! (c) 2009  Infineon Technologies AG, Munich
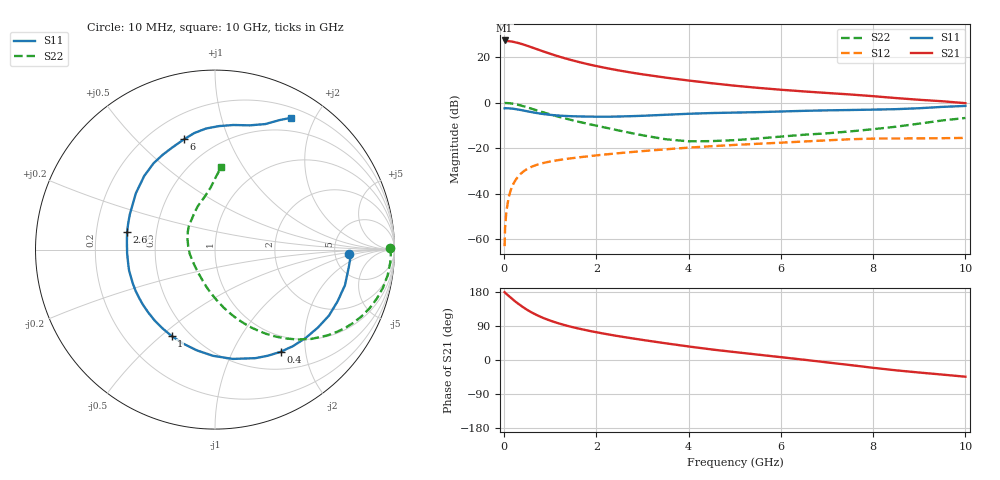
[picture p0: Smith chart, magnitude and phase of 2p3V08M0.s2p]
! Infineon Technologies  Discrete & RF Semiconductors
! BFP420
! VCE =  3.0 V,  IC =  8.0 mA
! Common Emitter S-Parameters:  Nov 2009
# GHz  S  MA  R  50
!  f  S11  S21  S12  S22
! GHz  MAG  ANG  MAG  ANG  MAG  ANG  MAG  ANG
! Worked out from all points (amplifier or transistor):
!   46 points, 10 MHz to 10 GHz, reference 50 ohm
!   highest |S21| = 27.3 dB at 10 MHz (marker M1)
!   |S21| within 3 dB of that: start of sweep to 594.4 MHz
!   unconditionally stable (mu >= 1): start of sweep to 10.1 MHz; 2.569 GHz to end of sweep
!   at 300 MHz: K = 0.16, MSG = 29.4 dB, |S12| = -32.6 dB
!   at 1.7 GHz: K = 0.75, MSG = 20.7 dB, |S12| = -23.9 dB
!   at 10 GHz: K = 1.10, MAG = 5.7 dB, |S12| = -15.5 dB
!   lowest NFmin = 0.79 dB at 900 MHz
!   S11 on the Smith chart (normalised r, x): 10 MHz: 6.91, -0.70; 400 MHz: 0.75, -1.57; 1 GHz: 0.40, -0.54; 2.6 GHz: 0.34, +0.09; 6 GHz: 0.34, +0.70; 10 GHz: 0.32, +1.68
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0.01  0.7496 -1.7  23.25 179.0  0.0007 60.7  0.9755 0.6
0.02  0.7566 -3.0  22.61 177.7  0.0018 79.4  0.9801 -1.6
0.05  0.7518 -7.5  22.56 174.3  0.0042 80.0  0.9794 -4.1
0.1  0.7508 -15.3  22.46 169.1  0.0085 80.8  0.9724 -8.5
0.2  0.7337 -30.1  21.67 158.7  0.0164 75.1  0.9424 -16.8
0.3  0.7055 -44.2  20.52 149.0  0.0235 69.0  0.8973 -24.5
0.4  0.6768 -57.3  19.17 140.3  0.0296 63.5  0.8436 -31.4
0.5  0.6456 -69.5  17.75 132.3  0.0348 58.9  0.7873 -37.4
0.7  0.592 -91.0  15.09 119.0  0.0427 51.8  0.6803 -47.4
0.8  0.5706 -100.2  13.88 113.4  0.0458 49.1  0.6329 -51.5
1  0.5387 -116.7  11.86 103.9  0.0508 45.2  0.5505 -58.6
1.3  0.511 -136.6  9.547 92.5  0.057 41.5  0.4549 -67.2
1.7  0.4954 -157.4  7.467 80.7  0.0641 38.4  0.3629 -76.9
2.2  0.4901 -177.7  5.784 68.7  0.0727 35.5  0.2815 -88.1
2.6  0.4994 168.8  4.872 60.5  0.0793 33.3  0.231 -98.3
3.5  0.5409 144.7  3.549 44.1  0.0942 28.3  0.1568 -128.3
4.5  0.5906 125.4  2.668 27.8  0.1103 21.7  0.1427 -170.0
5.5  0.6182 112.1  2.113 14.2  0.1246 15.1  0.1625 160.2
6  0.6384 105.7  1.92 7.5  0.1318 11.8  0.1793 148.0
7  0.6763 94.3  1.63 -6.3  0.1483 4.1  0.2114 128.3
8.5  0.7187 74.4  1.259 -27.3  0.163 -11.1  0.2958 101.9
10  0.8469 60.1  0.973 -44.1  0.1678 -21.2  0.4599 85.8
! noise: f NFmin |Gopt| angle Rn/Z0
0.9  0.79  0.08  30  0.13
1.8  1.14  0.06  171  0.12
2.4  1.24  0.1  160  0.13
3  1.32  0.17  -165  0.12
4  1.46  0.32  -132  0.14
5  1.85  0.39  -110  0.25
6  2.3  0.46  -95  0.37
